# Generated deterministically by seda-macro-lef-normalizer-v1; recipe orfs-asap7-fakeram-m4-v1.
VERSION 5.8 ;
BUSBITCHARS "[]" ;
DIVIDERCHAR "/" ;

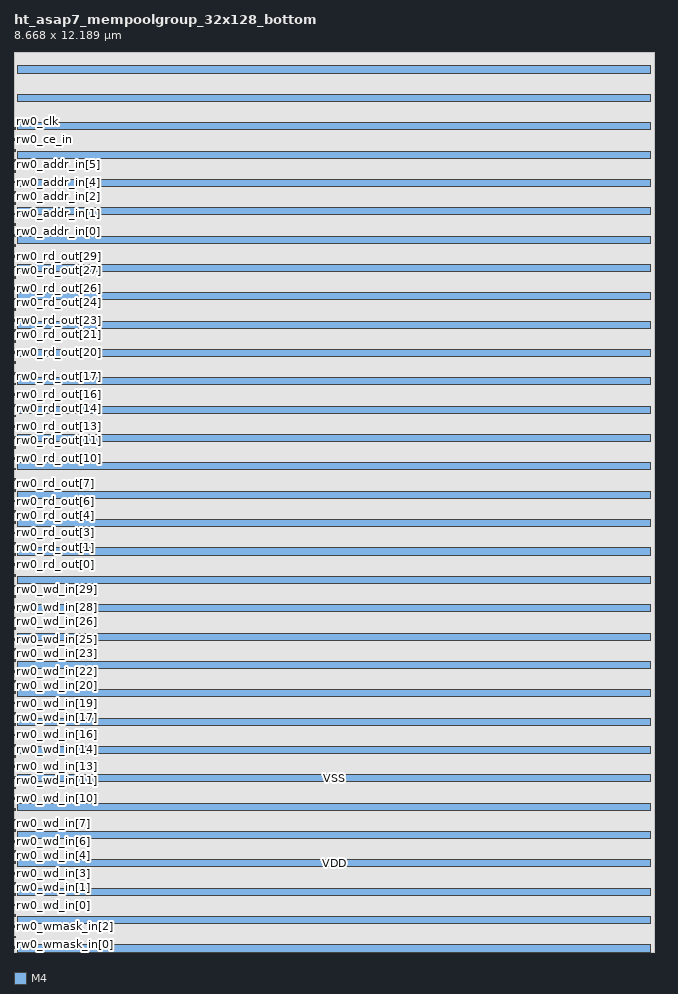
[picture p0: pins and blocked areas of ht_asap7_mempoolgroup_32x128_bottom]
MACRO ht_asap7_mempoolgroup_32x128_bottom
  FOREIGN ht_asap7_mempoolgroup_32x128_bottom 0 0 ;
  CLASS COVER ;
  ORIGIN 0 0 ;
  SIZE 8.668 BY 12.189 ;
  SYMMETRY X Y R90 ;
  PIN rw0_wmask_in[0]
    DIRECTION INPUT ;
    USE SIGNAL ;
    SHAPE ABUTMENT ;
    PORT
      LAYER M4 ;
      RECT 0 0.048 0.024 0.072 ;
    END
  END rw0_wmask_in[0]
  PIN rw0_wmask_in[1]
    DIRECTION INPUT ;
    USE SIGNAL ;
    SHAPE ABUTMENT ;
    PORT
      LAYER M4 ;
      RECT 0 0.192 0.024 0.216 ;
    END
  END rw0_wmask_in[1]
  PIN rw0_wmask_in[2]
    DIRECTION INPUT ;
    USE SIGNAL ;
    SHAPE ABUTMENT ;
    PORT
      LAYER M4 ;
      RECT 0 0.336 0.024 0.36 ;
    END
  END rw0_wmask_in[2]
  PIN rw0_wmask_in[3]
    DIRECTION INPUT ;
    USE SIGNAL ;
    SHAPE ABUTMENT ;
    PORT
      LAYER M4 ;
      RECT 0 0.48 0.024 0.504 ;
    END
  END rw0_wmask_in[3]
  PIN rw0_wd_in[0]
    DIRECTION INPUT ;
    USE SIGNAL ;
    SHAPE ABUTMENT ;
    PORT
      LAYER M4 ;
      RECT 0 0.624 0.024 0.648 ;
    END
  END rw0_wd_in[0]
  PIN rw0_wd_in[1]
    DIRECTION INPUT ;
    USE SIGNAL ;
    SHAPE ABUTMENT ;
    PORT
      LAYER M4 ;
      RECT 0 0.768 0.024 0.792 ;
    END
  END rw0_wd_in[1]
  PIN rw0_wd_in[2]
    DIRECTION INPUT ;
    USE SIGNAL ;
    SHAPE ABUTMENT ;
    PORT
      LAYER M4 ;
      RECT 0 0.912 0.024 0.936 ;
    END
  END rw0_wd_in[2]
  PIN rw0_wd_in[3]
    DIRECTION INPUT ;
    USE SIGNAL ;
    SHAPE ABUTMENT ;
    PORT
      LAYER M4 ;
      RECT 0 1.056 0.024 1.08 ;
    END
  END rw0_wd_in[3]
  PIN rw0_wd_in[4]
    DIRECTION INPUT ;
    USE SIGNAL ;
    SHAPE ABUTMENT ;
    PORT
      LAYER M4 ;
      RECT 0 1.2 0.024 1.224 ;
    END
  END rw0_wd_in[4]
  PIN rw0_wd_in[5]
    DIRECTION INPUT ;
    USE SIGNAL ;
    SHAPE ABUTMENT ;
    PORT
      LAYER M4 ;
      RECT 0 1.344 0.024 1.368 ;
    END
  END rw0_wd_in[5]
  PIN rw0_wd_in[6]
    DIRECTION INPUT ;
    USE SIGNAL ;
    SHAPE ABUTMENT ;
    PORT
      LAYER M4 ;
      RECT 0 1.488 0.024 1.512 ;
    END
  END rw0_wd_in[6]
  PIN rw0_wd_in[7]
    DIRECTION INPUT ;
    USE SIGNAL ;
    SHAPE ABUTMENT ;
    PORT
      LAYER M4 ;
      RECT 0 1.632 0.024 1.656 ;
    END
  END rw0_wd_in[7]
  PIN rw0_wd_in[8]
    DIRECTION INPUT ;
    USE SIGNAL ;
    SHAPE ABUTMENT ;
    PORT
      LAYER M4 ;
      RECT 0 1.776 0.024 1.8 ;
    END
  END rw0_wd_in[8]
  PIN rw0_wd_in[9]
    DIRECTION INPUT ;
    USE SIGNAL ;
    SHAPE ABUTMENT ;
    PORT
      LAYER M4 ;
      RECT 0 1.92 0.024 1.944 ;
    END
  END rw0_wd_in[9]
  PIN rw0_wd_in[10]
    DIRECTION INPUT ;
    USE SIGNAL ;
    SHAPE ABUTMENT ;
    PORT
      LAYER M4 ;
      RECT 0 2.064 0.024 2.088 ;
    END
  END rw0_wd_in[10]
  PIN rw0_wd_in[11]
    DIRECTION INPUT ;
    USE SIGNAL ;
    SHAPE ABUTMENT ;
    PORT
      LAYER M4 ;
      RECT 0 2.208 0.024 2.232 ;
    END
  END rw0_wd_in[11]
  PIN rw0_wd_in[12]
    DIRECTION INPUT ;
    USE SIGNAL ;
    SHAPE ABUTMENT ;
    PORT
      LAYER M4 ;
      RECT 0 2.352 0.024 2.376 ;
    END
  END rw0_wd_in[12]
  PIN rw0_wd_in[13]
    DIRECTION INPUT ;
    USE SIGNAL ;
    SHAPE ABUTMENT ;
    PORT
      LAYER M4 ;
      RECT 0 2.496 0.024 2.52 ;
    END
  END rw0_wd_in[13]
  PIN rw0_wd_in[14]
    DIRECTION INPUT ;
    USE SIGNAL ;
    SHAPE ABUTMENT ;
    PORT
      LAYER M4 ;
      RECT 0 2.64 0.024 2.664 ;
    END
  END rw0_wd_in[14]
  PIN rw0_wd_in[15]
    DIRECTION INPUT ;
    USE SIGNAL ;
    SHAPE ABUTMENT ;
    PORT
      LAYER M4 ;
      RECT 0 2.784 0.024 2.808 ;
    END
  END rw0_wd_in[15]
  PIN rw0_wd_in[16]
    DIRECTION INPUT ;
    USE SIGNAL ;
    SHAPE ABUTMENT ;
    PORT
      LAYER M4 ;
      RECT 0 2.928 0.024 2.952 ;
    END
  END rw0_wd_in[16]
  PIN rw0_wd_in[17]
    DIRECTION INPUT ;
    USE SIGNAL ;
    SHAPE ABUTMENT ;
    PORT
      LAYER M4 ;
      RECT 0 3.072 0.024 3.096 ;
    END
  END rw0_wd_in[17]
  PIN rw0_wd_in[18]
    DIRECTION INPUT ;
    USE SIGNAL ;
    SHAPE ABUTMENT ;
    PORT
      LAYER M4 ;
      RECT 0 3.216 0.024 3.24 ;
    END
  END rw0_wd_in[18]
  PIN rw0_wd_in[19]
    DIRECTION INPUT ;
    USE SIGNAL ;
    SHAPE ABUTMENT ;
    PORT
      LAYER M4 ;
      RECT 0 3.36 0.024 3.384 ;
    END
  END rw0_wd_in[19]
  PIN rw0_wd_in[20]
    DIRECTION INPUT ;
    USE SIGNAL ;
    SHAPE ABUTMENT ;
    PORT
      LAYER M4 ;
      RECT 0 3.504 0.024 3.528 ;
    END
  END rw0_wd_in[20]
  PIN rw0_wd_in[21]
    DIRECTION INPUT ;
    USE SIGNAL ;
    SHAPE ABUTMENT ;
    PORT
      LAYER M4 ;
      RECT 0 3.648 0.024 3.672 ;
    END
  END rw0_wd_in[21]
  PIN rw0_wd_in[22]
    DIRECTION INPUT ;
    USE SIGNAL ;
    SHAPE ABUTMENT ;
    PORT
      LAYER M4 ;
      RECT 0 3.792 0.024 3.816 ;
    END
  END rw0_wd_in[22]
  PIN rw0_wd_in[23]
    DIRECTION INPUT ;
    USE SIGNAL ;
    SHAPE ABUTMENT ;
    PORT
      LAYER M4 ;
      RECT 0 3.936 0.024 3.96 ;
    END
  END rw0_wd_in[23]
  PIN rw0_wd_in[24]
    DIRECTION INPUT ;
    USE SIGNAL ;
    SHAPE ABUTMENT ;
    PORT
      LAYER M4 ;
      RECT 0 4.08 0.024 4.104 ;
    END
  END rw0_wd_in[24]
  PIN rw0_wd_in[25]
    DIRECTION INPUT ;
    USE SIGNAL ;
    SHAPE ABUTMENT ;
    PORT
      LAYER M4 ;
      RECT 0 4.224 0.024 4.248 ;
    END
  END rw0_wd_in[25]
  PIN rw0_wd_in[26]
    DIRECTION INPUT ;
    USE SIGNAL ;
    SHAPE ABUTMENT ;
    PORT
      LAYER M4 ;
      RECT 0 4.368 0.024 4.392 ;
    END
  END rw0_wd_in[26]
  PIN rw0_wd_in[27]
    DIRECTION INPUT ;
    USE SIGNAL ;
    SHAPE ABUTMENT ;
    PORT
      LAYER M4 ;
      RECT 0 4.512 0.024 4.536 ;
    END
  END rw0_wd_in[27]
  PIN rw0_wd_in[28]
    DIRECTION INPUT ;
    USE SIGNAL ;
    SHAPE ABUTMENT ;
    PORT
      LAYER M4 ;
      RECT 0 4.656 0.024 4.68 ;
    END
  END rw0_wd_in[28]
  PIN rw0_wd_in[29]
    DIRECTION INPUT ;
    USE SIGNAL ;
    SHAPE ABUTMENT ;
    PORT
      LAYER M4 ;
      RECT 0 4.8 0.024 4.824 ;
    END
  END rw0_wd_in[29]
  PIN rw0_wd_in[30]
    DIRECTION INPUT ;
    USE SIGNAL ;
    SHAPE ABUTMENT ;
    PORT
      LAYER M4 ;
      RECT 0 4.944 0.024 4.968 ;
    END
  END rw0_wd_in[30]
  PIN rw0_wd_in[31]
    DIRECTION INPUT ;
    USE SIGNAL ;
    SHAPE ABUTMENT ;
    PORT
      LAYER M4 ;
      RECT 0 5.088 0.024 5.112 ;
    END
  END rw0_wd_in[31]
  PIN rw0_rd_out[0]
    DIRECTION OUTPUT ;
    USE SIGNAL ;
    SHAPE ABUTMENT ;
    PORT
      LAYER M4 ;
      RECT 0 5.232 0.024 5.256 ;
    END
  END rw0_rd_out[0]
  PIN rw0_rd_out[1]
    DIRECTION OUTPUT ;
    USE SIGNAL ;
    SHAPE ABUTMENT ;
    PORT
      LAYER M4 ;
      RECT 0 5.376 0.024 5.4 ;
    END
  END rw0_rd_out[1]
  PIN rw0_rd_out[2]
    DIRECTION OUTPUT ;
    USE SIGNAL ;
    SHAPE ABUTMENT ;
    PORT
      LAYER M4 ;
      RECT 0 5.52 0.024 5.544 ;
    END
  END rw0_rd_out[2]
  PIN rw0_rd_out[3]
    DIRECTION OUTPUT ;
    USE SIGNAL ;
    SHAPE ABUTMENT ;
    PORT
      LAYER M4 ;
      RECT 0 5.664 0.024 5.688 ;
    END
  END rw0_rd_out[3]
  PIN rw0_rd_out[4]
    DIRECTION OUTPUT ;
    USE SIGNAL ;
    SHAPE ABUTMENT ;
    PORT
      LAYER M4 ;
      RECT 0 5.808 0.024 5.832 ;
    END
  END rw0_rd_out[4]
  PIN rw0_rd_out[5]
    DIRECTION OUTPUT ;
    USE SIGNAL ;
    SHAPE ABUTMENT ;
    PORT
      LAYER M4 ;
      RECT 0 5.952 0.024 5.976 ;
    END
  END rw0_rd_out[5]
  PIN rw0_rd_out[6]
    DIRECTION OUTPUT ;
    USE SIGNAL ;
    SHAPE ABUTMENT ;
    PORT
      LAYER M4 ;
      RECT 0 6.096 0.024 6.12 ;
    END
  END rw0_rd_out[6]
  PIN rw0_rd_out[7]
    DIRECTION OUTPUT ;
    USE SIGNAL ;
    SHAPE ABUTMENT ;
    PORT
      LAYER M4 ;
      RECT 0 6.24 0.024 6.264 ;
    END
  END rw0_rd_out[7]
  PIN rw0_rd_out[8]
    DIRECTION OUTPUT ;
    USE SIGNAL ;
    SHAPE ABUTMENT ;
    PORT
      LAYER M4 ;
      RECT 0 6.384 0.024 6.408 ;
    END
  END rw0_rd_out[8]
  PIN rw0_rd_out[9]
    DIRECTION OUTPUT ;
    USE SIGNAL ;
    SHAPE ABUTMENT ;
    PORT
      LAYER M4 ;
      RECT 0 6.528 0.024 6.552 ;
    END
  END rw0_rd_out[9]
  PIN rw0_rd_out[10]
    DIRECTION OUTPUT ;
    USE SIGNAL ;
    SHAPE ABUTMENT ;
    PORT
      LAYER M4 ;
      RECT 0 6.672 0.024 6.696 ;
    END
  END rw0_rd_out[10]
  PIN rw0_rd_out[11]
    DIRECTION OUTPUT ;
    USE SIGNAL ;
    SHAPE ABUTMENT ;
    PORT
      LAYER M4 ;
      RECT 0 6.816 0.024 6.84 ;
    END
  END rw0_rd_out[11]
  PIN rw0_rd_out[12]
    DIRECTION OUTPUT ;
    USE SIGNAL ;
    SHAPE ABUTMENT ;
    PORT
      LAYER M4 ;
      RECT 0 6.96 0.024 6.984 ;
    END
  END rw0_rd_out[12]
  PIN rw0_rd_out[13]
    DIRECTION OUTPUT ;
    USE SIGNAL ;
    SHAPE ABUTMENT ;
    PORT
      LAYER M4 ;
      RECT 0 7.104 0.024 7.128 ;
    END
  END rw0_rd_out[13]
  PIN rw0_rd_out[14]
    DIRECTION OUTPUT ;
    USE SIGNAL ;
    SHAPE ABUTMENT ;
    PORT
      LAYER M4 ;
      RECT 0 7.248 0.024 7.272 ;
    END
  END rw0_rd_out[14]
  PIN rw0_rd_out[15]
    DIRECTION OUTPUT ;
    USE SIGNAL ;
    SHAPE ABUTMENT ;
    PORT
      LAYER M4 ;
      RECT 0 7.392 0.024 7.416 ;
    END
  END rw0_rd_out[15]
  PIN rw0_rd_out[16]
    DIRECTION OUTPUT ;
    USE SIGNAL ;
    SHAPE ABUTMENT ;
    PORT
      LAYER M4 ;
      RECT 0 7.536 0.024 7.56 ;
    END
  END rw0_rd_out[16]
  PIN rw0_rd_out[17]
    DIRECTION OUTPUT ;
    USE SIGNAL ;
    SHAPE ABUTMENT ;
    PORT
      LAYER M4 ;
      RECT 0 7.68 0.024 7.704 ;
    END
  END rw0_rd_out[17]
  PIN rw0_rd_out[18]
    DIRECTION OUTPUT ;
    USE SIGNAL ;
    SHAPE ABUTMENT ;
    PORT
      LAYER M4 ;
      RECT 0 7.824 0.024 7.848 ;
    END
  END rw0_rd_out[18]
  PIN rw0_rd_out[19]
    DIRECTION OUTPUT ;
    USE SIGNAL ;
    SHAPE ABUTMENT ;
    PORT
      LAYER M4 ;
      RECT 0 7.968 0.024 7.992 ;
    END
  END rw0_rd_out[19]
  PIN rw0_rd_out[20]
    DIRECTION OUTPUT ;
    USE SIGNAL ;
    SHAPE ABUTMENT ;
    PORT
      LAYER M4 ;
      RECT 0 8.112 0.024 8.136 ;
    END
  END rw0_rd_out[20]
  PIN rw0_rd_out[21]
    DIRECTION OUTPUT ;
    USE SIGNAL ;
    SHAPE ABUTMENT ;
    PORT
      LAYER M4 ;
      RECT 0 8.256 0.024 8.28 ;
    END
  END rw0_rd_out[21]
  PIN rw0_rd_out[22]
    DIRECTION OUTPUT ;
    USE SIGNAL ;
    SHAPE ABUTMENT ;
    PORT
      LAYER M4 ;
      RECT 0 8.4 0.024 8.424 ;
    END
  END rw0_rd_out[22]
  PIN rw0_rd_out[23]
    DIRECTION OUTPUT ;
    USE SIGNAL ;
    SHAPE ABUTMENT ;
    PORT
      LAYER M4 ;
      RECT 0 8.544 0.024 8.568 ;
    END
  END rw0_rd_out[23]
  PIN rw0_rd_out[24]
    DIRECTION OUTPUT ;
    USE SIGNAL ;
    SHAPE ABUTMENT ;
    PORT
      LAYER M4 ;
      RECT 0 8.688 0.024 8.712 ;
    END
  END rw0_rd_out[24]
  PIN rw0_rd_out[25]
    DIRECTION OUTPUT ;
    USE SIGNAL ;
    SHAPE ABUTMENT ;
    PORT
      LAYER M4 ;
      RECT 0 8.832 0.024 8.856 ;
    END
  END rw0_rd_out[25]
  PIN rw0_rd_out[26]
    DIRECTION OUTPUT ;
    USE SIGNAL ;
    SHAPE ABUTMENT ;
    PORT
      LAYER M4 ;
      RECT 0 8.976 0.024 9 ;
    END
  END rw0_rd_out[26]
  PIN rw0_rd_out[27]
    DIRECTION OUTPUT ;
    USE SIGNAL ;
    SHAPE ABUTMENT ;
    PORT
      LAYER M4 ;
      RECT 0 9.12 0.024 9.144 ;
    END
  END rw0_rd_out[27]
  PIN rw0_rd_out[28]
    DIRECTION OUTPUT ;
    USE SIGNAL ;
    SHAPE ABUTMENT ;
    PORT
      LAYER M4 ;
      RECT 0 9.264 0.024 9.288 ;
    END
  END rw0_rd_out[28]
  PIN rw0_rd_out[29]
    DIRECTION OUTPUT ;
    USE SIGNAL ;
    SHAPE ABUTMENT ;
    PORT
      LAYER M4 ;
      RECT 0 9.408 0.024 9.432 ;
    END
  END rw0_rd_out[29]
  PIN rw0_rd_out[30]
    DIRECTION OUTPUT ;
    USE SIGNAL ;
    SHAPE ABUTMENT ;
    PORT
      LAYER M4 ;
      RECT 0 9.552 0.024 9.576 ;
    END
  END rw0_rd_out[30]
  PIN rw0_rd_out[31]
    DIRECTION OUTPUT ;
    USE SIGNAL ;
    SHAPE ABUTMENT ;
    PORT
      LAYER M4 ;
      RECT 0 9.696 0.024 9.72 ;
    END
  END rw0_rd_out[31]
  PIN rw0_addr_in[0]
    DIRECTION INPUT ;
    USE SIGNAL ;
    SHAPE ABUTMENT ;
    PORT
      LAYER M4 ;
      RECT 0 9.84 0.024 9.864 ;
    END
  END rw0_addr_in[0]
  PIN rw0_addr_in[1]
    DIRECTION INPUT ;
    USE SIGNAL ;
    SHAPE ABUTMENT ;
    PORT
      LAYER M4 ;
      RECT 0 9.984 0.024 10.008 ;
    END
  END rw0_addr_in[1]
  PIN rw0_addr_in[2]
    DIRECTION INPUT ;
    USE SIGNAL ;
    SHAPE ABUTMENT ;
    PORT
      LAYER M4 ;
      RECT 0 10.128 0.024 10.152 ;
    END
  END rw0_addr_in[2]
  PIN rw0_addr_in[3]
    DIRECTION INPUT ;
    USE SIGNAL ;
    SHAPE ABUTMENT ;
    PORT
      LAYER M4 ;
      RECT 0 10.272 0.024 10.296 ;
    END
  END rw0_addr_in[3]
  PIN rw0_addr_in[4]
    DIRECTION INPUT ;
    USE SIGNAL ;
    SHAPE ABUTMENT ;
    PORT
      LAYER M4 ;
      RECT 0 10.416 0.024 10.44 ;
    END
  END rw0_addr_in[4]
  PIN rw0_addr_in[5]
    DIRECTION INPUT ;
    USE SIGNAL ;
    SHAPE ABUTMENT ;
    PORT
      LAYER M4 ;
      RECT 0 10.56 0.024 10.584 ;
    END
  END rw0_addr_in[5]
  PIN rw0_addr_in[6]
    DIRECTION INPUT ;
    USE SIGNAL ;
    SHAPE ABUTMENT ;
    PORT
      LAYER M4 ;
      RECT 0 10.704 0.024 10.728 ;
    END
  END rw0_addr_in[6]
  PIN rw0_we_in
    DIRECTION INPUT ;
    USE SIGNAL ;
    SHAPE ABUTMENT ;
    PORT
      LAYER M4 ;
      RECT 0 10.848 0.024 10.872 ;
    END
  END rw0_we_in
  PIN rw0_ce_in
    DIRECTION INPUT ;
    USE SIGNAL ;
    SHAPE ABUTMENT ;
    PORT
      LAYER M4 ;
      RECT 0 10.992 0.024 11.016 ;
    END
  END rw0_ce_in
  PIN rw0_clk
    DIRECTION INPUT ;
    USE SIGNAL ;
    SHAPE ABUTMENT ;
    PORT
      LAYER M4 ;
      RECT 0 11.136 0.024 11.16 ;
    END
  END rw0_clk
  PIN VSS
    DIRECTION INOUT ;
    USE GROUND ;
    PORT
      LAYER M4 ;
      RECT 0.048 0 8.62 0.096 ;
      RECT 0.048 0.768 8.62 0.864 ;
      RECT 0.048 1.536 8.62 1.632 ;
      RECT 0.048 2.304 8.62 2.4 ;
      RECT 0.048 3.072 8.62 3.168 ;
      RECT 0.048 3.84 8.62 3.936 ;
      RECT 0.048 4.608 8.62 4.704 ;
      RECT 0.048 5.376 8.62 5.472 ;
      RECT 0.048 6.144 8.62 6.24 ;
      RECT 0.048 6.912 8.62 7.008 ;
      RECT 0.048 7.68 8.62 7.776 ;
      RECT 0.048 8.448 8.62 8.544 ;
      RECT 0.048 9.216 8.62 9.312 ;
      RECT 0.048 9.984 8.62 10.08 ;
      RECT 0.048 10.752 8.62 10.848 ;
      RECT 0.048 11.52 8.62 11.616 ;
    END
  END VSS
  PIN VDD
    DIRECTION INOUT ;
    USE POWER ;
    PORT
      LAYER M4 ;
      RECT 0.048 0.384 8.62 0.48 ;
      RECT 0.048 1.152 8.62 1.248 ;
      RECT 0.048 1.92 8.62 2.016 ;
      RECT 0.048 2.688 8.62 2.784 ;
      RECT 0.048 3.456 8.62 3.552 ;
      RECT 0.048 4.224 8.62 4.32 ;
      RECT 0.048 4.992 8.62 5.088 ;
      RECT 0.048 5.76 8.62 5.856 ;
      RECT 0.048 6.528 8.62 6.624 ;
      RECT 0.048 7.296 8.62 7.392 ;
      RECT 0.048 8.064 8.62 8.16 ;
      RECT 0.048 8.832 8.62 8.928 ;
      RECT 0.048 9.6 8.62 9.696 ;
      RECT 0.048 10.368 8.62 10.464 ;
      RECT 0.048 11.136 8.62 11.232 ;
      RECT 0.048 11.904 8.62 12 ;
    END
  END VDD
  OBS
    LAYER M1 ;
    RECT 0 0 8.668 12.189 ;
    LAYER M2 ;
    RECT 0 0 8.668 12.189 ;
    LAYER M3 ;
    RECT 0 0 8.668 12.189 ;
  END
END ht_asap7_mempoolgroup_32x128_bottom

END LIBRARY
